VERSION 5.7 ;
  NOWIREEXTENSIONATPIN ON ;
  DIVIDERCHAR "/" ;
  BUSBITCHARS "[]" ;
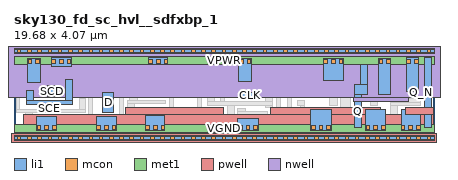
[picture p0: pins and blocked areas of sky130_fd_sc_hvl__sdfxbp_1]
MACRO sky130_fd_sc_hvl__sdfxbp_1
  CLASS BLOCK ;
  FOREIGN sky130_fd_sc_hvl__sdfxbp_1 ;
  ORIGIN 0.000 0.000 ;
  SIZE 19.680 BY 4.070 ;
  PIN CLK
    ANTENNAGATEAREA 0.585000 ;
    PORT
      LAYER li1 ;
        RECT 10.685 1.895 11.395 2.120 ;
    END
  END CLK
  PIN D
    ANTENNAGATEAREA 0.420000 ;
    PORT
      LAYER li1 ;
        RECT 4.165 1.175 4.675 2.150 ;
    END
  END D
  PIN SCD
    ANTENNAGATEAREA 0.420000 ;
    PORT
      LAYER li1 ;
        RECT 1.565 1.930 1.975 2.440 ;
    END
  END SCD
  PIN SCE
    ANTENNAGATEAREA 0.840000 ;
    PORT
      LAYER li1 ;
        RECT 0.565 1.750 0.895 2.220 ;
        RECT 2.425 1.750 2.755 2.745 ;
        RECT 0.565 1.550 2.755 1.750 ;
    END
  END SCE
  PIN VGND
    USE GROUND ;
    PORT
      LAYER li1 ;
        RECT 1.050 0.365 2.000 0.995 ;
        RECT 3.860 0.365 4.785 0.995 ;
        RECT 6.175 0.365 7.065 1.075 ;
        RECT 10.495 0.365 11.445 0.915 ;
        RECT 13.915 0.365 14.865 1.325 ;
        RECT 16.465 0.365 17.415 1.325 ;
        RECT 18.140 0.365 19.040 1.325 ;
      LAYER mcon ;
        RECT 1.080 0.395 1.250 0.565 ;
        RECT 1.440 0.395 1.610 0.565 ;
        RECT 1.800 0.395 1.970 0.565 ;
        RECT 3.875 0.395 4.045 0.565 ;
        RECT 4.235 0.395 4.405 0.565 ;
        RECT 4.595 0.395 4.765 0.565 ;
        RECT 6.175 0.395 6.345 0.565 ;
        RECT 6.535 0.395 6.705 0.565 ;
        RECT 6.895 0.395 7.065 0.565 ;
        RECT 10.525 0.395 10.695 0.565 ;
        RECT 10.885 0.395 11.055 0.565 ;
        RECT 11.245 0.395 11.415 0.565 ;
        RECT 13.945 0.395 14.115 0.565 ;
        RECT 14.305 0.395 14.475 0.565 ;
        RECT 14.665 0.395 14.835 0.565 ;
        RECT 16.495 0.395 16.665 0.565 ;
        RECT 16.855 0.395 17.025 0.565 ;
        RECT 17.215 0.395 17.385 0.565 ;
        RECT 18.145 0.395 18.315 0.565 ;
        RECT 18.505 0.395 18.675 0.565 ;
        RECT 18.865 0.395 19.035 0.565 ;
      LAYER met1 ;
        RECT 0.000 0.255 19.680 0.625 ;
    END
  END VGND
  PIN VNB
    ANTENNADIFFAREA 3.345600 ;
    PORT
      LAYER pwell ;
        RECT 7.725 1.415 9.835 1.450 ;
        RECT 5.205 1.085 9.835 1.415 ;
        RECT 12.040 1.085 17.175 1.415 ;
        RECT 18.330 1.085 19.660 1.415 ;
        RECT 0.430 0.215 19.660 1.085 ;
        RECT -0.130 -0.215 19.810 0.215 ;
      LAYER li1 ;
        RECT 0.000 -0.085 19.680 0.085 ;
      LAYER mcon ;
        RECT 0.155 -0.085 0.325 0.085 ;
        RECT 0.635 -0.085 0.805 0.085 ;
        RECT 1.115 -0.085 1.285 0.085 ;
        RECT 1.595 -0.085 1.765 0.085 ;
        RECT 2.075 -0.085 2.245 0.085 ;
        RECT 2.555 -0.085 2.725 0.085 ;
        RECT 3.035 -0.085 3.205 0.085 ;
        RECT 3.515 -0.085 3.685 0.085 ;
        RECT 3.995 -0.085 4.165 0.085 ;
        RECT 4.475 -0.085 4.645 0.085 ;
        RECT 4.955 -0.085 5.125 0.085 ;
        RECT 5.435 -0.085 5.605 0.085 ;
        RECT 5.915 -0.085 6.085 0.085 ;
        RECT 6.395 -0.085 6.565 0.085 ;
        RECT 6.875 -0.085 7.045 0.085 ;
        RECT 7.355 -0.085 7.525 0.085 ;
        RECT 7.835 -0.085 8.005 0.085 ;
        RECT 8.315 -0.085 8.485 0.085 ;
        RECT 8.795 -0.085 8.965 0.085 ;
        RECT 9.275 -0.085 9.445 0.085 ;
        RECT 9.755 -0.085 9.925 0.085 ;
        RECT 10.235 -0.085 10.405 0.085 ;
        RECT 10.715 -0.085 10.885 0.085 ;
        RECT 11.195 -0.085 11.365 0.085 ;
        RECT 11.675 -0.085 11.845 0.085 ;
        RECT 12.155 -0.085 12.325 0.085 ;
        RECT 12.635 -0.085 12.805 0.085 ;
        RECT 13.115 -0.085 13.285 0.085 ;
        RECT 13.595 -0.085 13.765 0.085 ;
        RECT 14.075 -0.085 14.245 0.085 ;
        RECT 14.555 -0.085 14.725 0.085 ;
        RECT 15.035 -0.085 15.205 0.085 ;
        RECT 15.515 -0.085 15.685 0.085 ;
        RECT 15.995 -0.085 16.165 0.085 ;
        RECT 16.475 -0.085 16.645 0.085 ;
        RECT 16.955 -0.085 17.125 0.085 ;
        RECT 17.435 -0.085 17.605 0.085 ;
        RECT 17.915 -0.085 18.085 0.085 ;
        RECT 18.395 -0.085 18.565 0.085 ;
        RECT 18.875 -0.085 19.045 0.085 ;
        RECT 19.355 -0.085 19.525 0.085 ;
      LAYER met1 ;
        RECT 0.000 -0.115 19.680 0.115 ;
    END
  END VNB
  PIN VPB
    ANTENNADIFFAREA 3.345600 ;
    PORT
      LAYER nwell ;
        RECT -0.330 1.885 20.010 4.485 ;
        RECT 15.925 1.715 18.490 1.885 ;
      LAYER li1 ;
        RECT 0.000 3.985 19.680 4.155 ;
      LAYER mcon ;
        RECT 0.155 3.985 0.325 4.155 ;
        RECT 0.635 3.985 0.805 4.155 ;
        RECT 1.115 3.985 1.285 4.155 ;
        RECT 1.595 3.985 1.765 4.155 ;
        RECT 2.075 3.985 2.245 4.155 ;
        RECT 2.555 3.985 2.725 4.155 ;
        RECT 3.035 3.985 3.205 4.155 ;
        RECT 3.515 3.985 3.685 4.155 ;
        RECT 3.995 3.985 4.165 4.155 ;
        RECT 4.475 3.985 4.645 4.155 ;
        RECT 4.955 3.985 5.125 4.155 ;
        RECT 5.435 3.985 5.605 4.155 ;
        RECT 5.915 3.985 6.085 4.155 ;
        RECT 6.395 3.985 6.565 4.155 ;
        RECT 6.875 3.985 7.045 4.155 ;
        RECT 7.355 3.985 7.525 4.155 ;
        RECT 7.835 3.985 8.005 4.155 ;
        RECT 8.315 3.985 8.485 4.155 ;
        RECT 8.795 3.985 8.965 4.155 ;
        RECT 9.275 3.985 9.445 4.155 ;
        RECT 9.755 3.985 9.925 4.155 ;
        RECT 10.235 3.985 10.405 4.155 ;
        RECT 10.715 3.985 10.885 4.155 ;
        RECT 11.195 3.985 11.365 4.155 ;
        RECT 11.675 3.985 11.845 4.155 ;
        RECT 12.155 3.985 12.325 4.155 ;
        RECT 12.635 3.985 12.805 4.155 ;
        RECT 13.115 3.985 13.285 4.155 ;
        RECT 13.595 3.985 13.765 4.155 ;
        RECT 14.075 3.985 14.245 4.155 ;
        RECT 14.555 3.985 14.725 4.155 ;
        RECT 15.035 3.985 15.205 4.155 ;
        RECT 15.515 3.985 15.685 4.155 ;
        RECT 15.995 3.985 16.165 4.155 ;
        RECT 16.475 3.985 16.645 4.155 ;
        RECT 16.955 3.985 17.125 4.155 ;
        RECT 17.435 3.985 17.605 4.155 ;
        RECT 17.915 3.985 18.085 4.155 ;
        RECT 18.395 3.985 18.565 4.155 ;
        RECT 18.875 3.985 19.045 4.155 ;
        RECT 19.355 3.985 19.525 4.155 ;
      LAYER met1 ;
        RECT 0.000 3.955 19.680 4.185 ;
    END
  END VPB
  PIN VPWR
    USE POWER ;
    PORT
      LAYER li1 ;
        RECT 0.630 2.620 1.220 3.705 ;
        RECT 1.750 3.335 2.700 3.755 ;
        RECT 6.320 3.465 7.210 3.755 ;
        RECT 10.535 2.650 11.125 3.705 ;
        RECT 14.520 2.695 15.425 3.735 ;
        RECT 17.075 2.025 17.665 3.705 ;
        RECT 18.380 2.175 18.970 3.755 ;
      LAYER mcon ;
        RECT 0.660 3.505 0.830 3.675 ;
        RECT 1.020 3.505 1.190 3.675 ;
        RECT 1.780 3.505 1.950 3.675 ;
        RECT 2.140 3.505 2.310 3.675 ;
        RECT 2.500 3.505 2.670 3.675 ;
        RECT 6.320 3.505 6.490 3.675 ;
        RECT 6.680 3.505 6.850 3.675 ;
        RECT 7.040 3.505 7.210 3.675 ;
        RECT 10.565 3.505 10.735 3.675 ;
        RECT 10.925 3.505 11.095 3.675 ;
        RECT 14.525 3.505 14.695 3.675 ;
        RECT 14.885 3.505 15.055 3.675 ;
        RECT 15.245 3.505 15.415 3.675 ;
        RECT 17.105 3.505 17.275 3.675 ;
        RECT 17.465 3.505 17.635 3.675 ;
        RECT 18.410 3.505 18.580 3.675 ;
        RECT 18.770 3.505 18.940 3.675 ;
      LAYER met1 ;
        RECT 0.000 3.445 19.680 3.815 ;
    END
  END VPWR
  PIN Q
    ANTENNADIFFAREA 0.611250 ;
    PORT
      LAYER li1 ;
        RECT 16.215 2.515 16.545 3.455 ;
        RECT 15.955 2.025 16.545 2.515 ;
        RECT 15.955 0.495 16.285 2.025 ;
    END
  END Q
  PIN Q_N
    ANTENNADIFFAREA 0.641250 ;
    PORT
      LAYER li1 ;
        RECT 19.220 0.495 19.555 3.755 ;
    END
  END Q_N
  OBS
      LAYER li1 ;
        RECT 1.400 3.095 1.570 3.755 ;
        RECT 2.880 3.610 4.030 3.780 ;
        RECT 2.880 3.275 3.210 3.610 ;
        RECT 3.430 3.095 3.680 3.430 ;
        RECT 0.110 2.555 0.440 3.015 ;
        RECT 1.400 2.925 3.680 3.095 ;
        RECT 3.860 2.850 4.030 3.610 ;
        RECT 4.210 3.635 6.140 3.805 ;
        RECT 4.210 3.030 4.540 3.635 ;
        RECT 4.990 2.850 5.240 3.430 ;
        RECT 3.860 2.680 5.240 2.850 ;
        RECT 0.110 1.345 0.280 2.555 ;
        RECT 3.510 2.330 5.135 2.500 ;
        RECT 3.065 1.345 3.330 1.845 ;
        RECT 0.110 1.175 3.330 1.345 ;
        RECT 0.540 0.495 0.870 1.175 ;
        RECT 3.510 0.995 3.680 2.330 ;
        RECT 2.810 0.825 3.680 0.995 ;
        RECT 2.810 0.495 3.140 0.825 ;
        RECT 4.965 0.435 5.135 2.330 ;
        RECT 5.420 1.775 5.790 3.455 ;
        RECT 5.970 3.285 6.140 3.635 ;
        RECT 11.785 3.635 14.340 3.805 ;
        RECT 7.390 3.285 9.435 3.455 ;
        RECT 5.970 3.115 7.560 3.285 ;
        RECT 5.970 2.125 6.140 3.115 ;
        RECT 7.740 2.855 8.655 3.105 ;
        RECT 9.105 3.100 9.435 3.285 ;
        RECT 7.740 2.555 7.910 2.855 ;
        RECT 8.835 2.750 10.355 2.920 ;
        RECT 8.835 2.675 9.005 2.750 ;
        RECT 6.320 2.305 7.910 2.555 ;
        RECT 8.090 2.485 9.005 2.675 ;
        RECT 9.675 2.320 10.005 2.570 ;
        RECT 10.185 2.470 10.355 2.750 ;
        RECT 11.315 2.470 11.565 3.110 ;
        RECT 7.740 2.135 8.785 2.305 ;
        RECT 5.970 1.955 7.470 2.125 ;
        RECT 5.315 1.605 7.120 1.775 ;
        RECT 5.315 0.615 5.645 1.605 ;
        RECT 7.300 1.425 7.470 1.955 ;
        RECT 5.825 1.255 8.165 1.425 ;
        RECT 5.825 0.435 5.995 1.255 ;
        RECT 7.245 0.760 7.575 1.075 ;
        RECT 7.835 0.940 8.165 1.255 ;
        RECT 8.615 1.360 8.785 2.135 ;
        RECT 9.070 1.715 9.400 2.215 ;
        RECT 9.675 1.715 9.845 2.320 ;
        RECT 10.185 2.300 11.565 2.470 ;
        RECT 10.185 2.140 10.355 2.300 ;
        RECT 11.785 2.205 12.115 3.635 ;
        RECT 12.310 3.285 13.795 3.455 ;
        RECT 10.025 1.895 10.355 2.140 ;
        RECT 11.800 1.715 12.130 2.025 ;
        RECT 9.070 1.545 12.130 1.715 ;
        RECT 8.615 0.940 8.945 1.360 ;
        RECT 9.395 0.760 9.725 1.360 ;
        RECT 7.245 0.590 9.725 0.760 ;
        RECT 9.985 0.495 10.315 1.545 ;
        RECT 11.800 1.445 12.130 1.545 ;
        RECT 10.495 1.265 10.825 1.365 ;
        RECT 10.495 1.095 11.875 1.265 ;
        RECT 12.310 1.245 12.480 3.285 ;
        RECT 12.660 2.205 12.990 3.105 ;
        RECT 13.440 2.265 13.795 3.285 ;
        RECT 14.010 2.695 14.340 3.635 ;
        RECT 15.605 3.635 16.895 3.805 ;
        RECT 15.605 2.695 15.995 3.635 ;
        RECT 15.605 2.515 15.775 2.695 ;
        RECT 14.465 2.265 15.775 2.515 ;
        RECT 11.625 0.645 11.875 1.095 ;
        RECT 12.150 0.825 12.480 1.245 ;
        RECT 12.820 2.085 12.990 2.205 ;
        RECT 12.820 1.915 15.135 2.085 ;
        RECT 12.820 1.325 12.990 1.915 ;
        RECT 13.280 1.505 13.610 1.735 ;
        RECT 14.805 1.545 15.135 1.915 ;
        RECT 12.820 0.825 13.260 1.325 ;
        RECT 13.440 0.645 13.610 1.505 ;
        RECT 11.625 0.475 13.610 0.645 ;
        RECT 15.315 0.495 15.775 2.265 ;
        RECT 16.725 1.835 16.895 3.635 ;
        RECT 17.870 2.025 18.200 2.815 ;
        RECT 18.030 1.835 18.200 2.025 ;
        RECT 16.725 1.505 17.055 1.835 ;
        RECT 18.030 1.675 19.040 1.835 ;
        RECT 17.630 1.505 19.040 1.675 ;
        RECT 17.630 0.495 17.960 1.505 ;
        RECT 4.965 0.265 5.995 0.435 ;
      LAYER mcon ;
        RECT 5.435 3.060 5.605 3.230 ;
        RECT 13.595 3.060 13.765 3.230 ;
      LAYER met1 ;
        RECT 5.375 3.215 5.665 3.260 ;
        RECT 13.535 3.215 13.825 3.260 ;
        RECT 5.375 3.075 13.825 3.215 ;
        RECT 5.375 3.030 5.665 3.075 ;
        RECT 13.535 3.030 13.825 3.075 ;
  END
END sky130_fd_sc_hvl__sdfxbp_1
END LIBRARY

